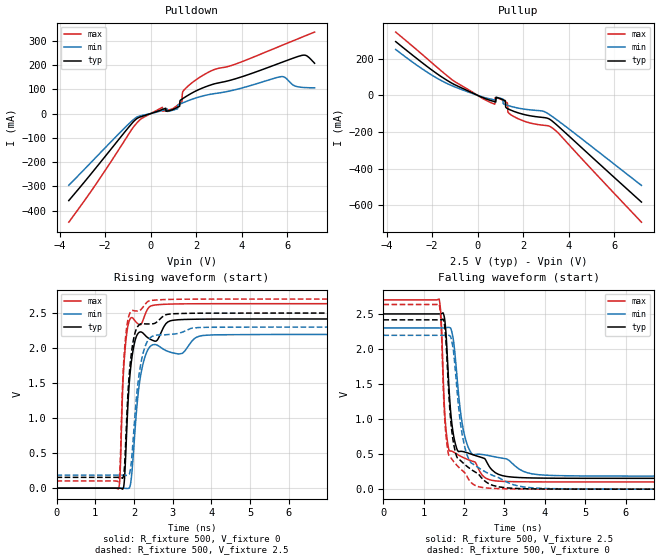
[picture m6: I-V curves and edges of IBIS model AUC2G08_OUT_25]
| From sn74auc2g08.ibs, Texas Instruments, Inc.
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[Model]   AUC2G08_OUT_25
Model_type  Output
Vref =   0
Rref =   500
Cref =   30p
Vmeas =   1.25
| variable   typ   min   max
C_comp   7.45pF   0.27pF   23.62pF
| C_pullup   8.36pF   0.27pF   23.62pF
| C_pulldown   6.53pF   1.89pF   15.75pF
[Temperature Range]   40   100   -40
| Ambient temperature   25   85   -40
[Voltage range]   2.5   2.3   2.7
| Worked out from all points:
|   slope of the pulldown table from 0 to 0.375 V, typ, clamps not added: 30.9 ohm
|   slope of the pullup table from 0 to 0.375 V, typ, clamps not added: 19.2 ohm
|   rising waveform, R_fixture 500, V_fixture 0: 20-80 % time 178ps typ, 248ps min, 131ps max; typ from 0 V to 2.42 V
|   falling waveform, R_fixture 500, V_fixture 2.5: 20-80 % time 223ps typ, 313ps min, 153ps max; typ from 2.5 V to 0.154 V
|   rising waveform, R_fixture 500, V_fixture 2.5: 20-80 % time 176ps typ, 247ps min, 129ps max; typ from 0.154 V to 2.5 V
|   falling waveform, R_fixture 500, V_fixture 0: 20-80 % time 238ps typ, 335ps min, 155ps max; typ from 2.42 V to 0 V
[Pulldown]
| AUC2G08_OUT_25
|   Voltage   I(typ)   I(min)   I(max)
-3.6V     -357.9mA   -295mA     -446.9mA
-445mV    -13.39mA   -9.086mA   -23.04mA
515mV     17.02mA    12.57mA    25.99mA
1.03V     19.04mA    15.49mA    23.85mA
1.27V     29.99mA    38.36mA    41.3mA
1.37V     59.29mA    42.41mA    48.87mA
1.395V    60.81mA    43.42mA    85.06mA
1.48V     65.92mA    46.77mA    98.72mA
2.545V    114.8mA    77.91mA    170.6mA
5.695V    208.4mA    151.5mA    277.8mA
6.74V     240.4mA    107.1mA    317.8mA
7.2V      207mA      105.9mA    335.2mA
[Pullup]
| AUC2G08_OUT_25
|   Voltage   I(typ)   I(min)   I(max)
-3.6V     293.6mA    250.5mA    345.5mA
-960mV    55.5mA     44.14mA    71.53mA
730mV     -33.82mA   -24.42mA   -47.21mA
760mV     -34.84mA   -25.13mA   -47.16mA
770mV     -35.18mA   -25.36mA   -13.07mA
1.115V    -23.84mA   -20.26mA   -27.67mA
1.215V    -28.81mA   -50.48mA   -34.67mA
1.295V    -71.05mA   -53.78mA   -40.2mA
1.345V    -74.3mA    -55.73mA   -93.3mA
1.755V    -94.43mA   -68.81mA   -126mA
3.31V     -143.6mA   -118mA     -180.4mA
7.2V      -582.7mA   -491.8mA   -692.5mA
[Ramp]
| AUC2G08_OUT_25
| variable   typ   min   max
dV/dt_r   1.46/1.79E-10   1.32/2.49E-10   1.59/1.31E-10
dV/dt_f   1.42/2.25E-10   1.27/3.13E-10   1.57/1.53E-10
R_load = 500
[Rising Waveform]
| AUC2G08_OUT_25
R_fixture =   500
C_fixture =   0
L_fixture =   0
V_fixture =   0
V_fixture_min = 0
V_fixture_max = 0
|   Time   V(typ)   V(min)   V(max)
0s        9.791nV    28.67nV    1.858nV
1.6ns     470.6uV    25.61uV    -8.929mV
1.64ns    -617.4uV   100.3uV    193.1mV
1.74ns    42.37mV    -167.3uV   1.761V
1.84ns    1.159V     -4.477mV   2.307V
1.93ns    1.795V     137.9mV    2.435V
2.055ns   2.156V     1.036V     2.37V
2.225ns   2.218V     1.756V     2.387V
2.485ns   2.11V      2.048V     2.609V
21.61ns   2.416V     2.195V     2.634V
[Falling Waveform]
| AUC2G08_OUT_25
R_fixture =   500
C_fixture =   0
L_fixture =   0
V_fixture =   2.5
V_fixture_min = 2.3
V_fixture_max = 2.7
|   Time   V(typ)   V(min)   V(max)
0s        2.5V       2.3V       2.7V
1.38ns    2.5V       2.3V       2.712V
1.435ns   2.503V     2.3V       2.376V
1.515ns   2.437V     2.299V     1.143V
1.62ns    1.496V     2.308V     567.3mV
1.785ns   644mV      1.859V     513mV
2.07ns    520.4mV    648.2mV    427.8mV
2.69ns    275mV      469.7mV    126.4mV
4.29ns    156.1mV    193.3mV    103.1mV
21.61ns   154.5mV    186.3mV    102.6mV
[Rising Waveform]
| AUC2G08_OUT_25
R_fixture =   500
C_fixture =   0
L_fixture =   0
V_fixture =   2.5
V_fixture_min = 2.3
V_fixture_max = 2.7
|   Time   V(typ)   V(min)   V(max)
0s        154.5mV    186.3mV    102.6mV
1.6ns     154.9mV    186.3mV    94.59mV
1.64ns    153.9mV    186.3mV    310.5mV
1.74ns    209.7mV    186.2mV    1.851V
1.83ns    1.207V     184mV      2.365V
1.915ns   1.843V     291mV      2.519V
2.025ns   2.213V     1.04V      2.531V
2.18ns    2.347V     1.789V     2.55V
2.4ns     2.345V     2.138V     2.675V
21.61ns   2.5V       2.3V       2.7V
[Falling Waveform]
| AUC2G08_OUT_25
R_fixture =   500
C_fixture =   0
L_fixture =   0
V_fixture =   0
V_fixture_min = 0
V_fixture_max = 0
|   Time   V(typ)   V(min)   V(max)
0s        2.416V     2.195V     2.634V
1.38ns    2.416V     2.195V     2.643V
1.435ns   2.417V     2.195V     2.288V
1.515ns   2.337V     2.194V     1.042V
1.61ns    1.472V     2.198V     502.7mV
1.815ns   467.1mV    1.48V      344.1mV
2.04ns    340.8mV    549.9mV    219.6mV
2.4ns     184.5mV    289.5mV    29.19mV
4.12ns    1.898mV    7.856mV    510.6uV
21.61ns   20.61uV    2.054uV    9.464uV
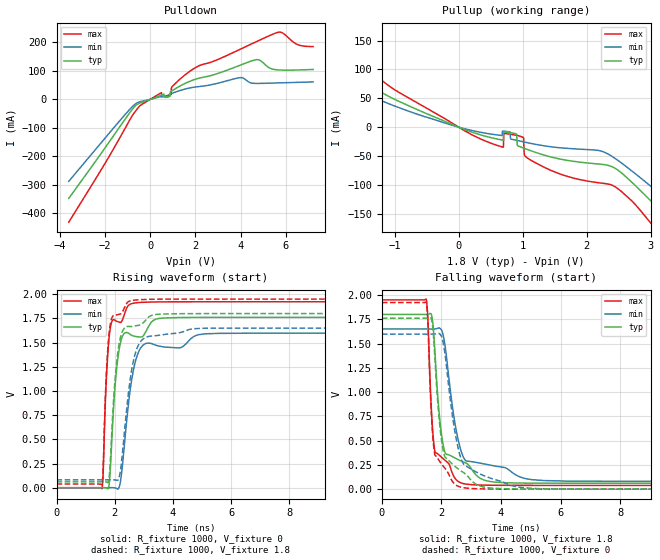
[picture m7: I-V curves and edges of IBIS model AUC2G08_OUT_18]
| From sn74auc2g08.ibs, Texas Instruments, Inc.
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[Model]   AUC2G08_OUT_18
Model_type  Output
Vref =   0
Rref =   1000
Cref =   30p
Vmeas =   0.9
| variable   typ   min   max
C_comp   6.69pF   0.25pF   21.38pF
| C_pullup   7.14pF   1.04pF   21.38pF
| C_pulldown   6.24pF   0.25pF   15.43pF
[Temperature Range]   40   100   -40
| Ambient temperature   25   85   -40
[Voltage range]   1.8   1.65   1.95
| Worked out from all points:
|   slope of the pulldown table from 0 to 0.27 V, typ, clamps not added: 34.4 ohm
|   slope of the pullup table from 0 to 0.27 V, typ, clamps not added: 24.7 ohm
|   rising waveform, R_fixture 1000, V_fixture 0: 20-80 % time 265ps typ, 394ps min, 176ps max; typ from 0 V to 1.76 V
|   falling waveform, R_fixture 1000, V_fixture 1.8: 20-80 % time 316ps typ, 478ps min, 197ps max; typ from 1.8 V to 0.061 V
|   rising waveform, R_fixture 1000, V_fixture 1.8: 20-80 % time 261ps typ, 385ps min, 173ps max; typ from 0.061 V to 1.8 V
|   falling waveform, R_fixture 1000, V_fixture 0: 20-80 % time 325ps typ, 487ps min, 197ps max; typ from 1.76 V to 0 V
[Pulldown]
| AUC2G08_OUT_18
|   Voltage   I(typ)   I(min)   I(max)
-3.6V     -347.6mA   -287.8mA   -431.2mA
-830mV    -38.94mA   -28.94mA   -62.22mA
-405mV    -11.33mA   -7.446mA   -19.55mA
495mV     14.95mA    10.62mA    23.51mA
885mV     12.26mA    19.06mA    15.87mA
925mV     28.54mA    20.16mA    16.88mA
960mV     30.1mA     21.15mA    44.31mA
2.045V    71.87mA    43.99mA    113.3mA
3.92V     118.2mA    75.85mA    173.7mA
4.625V    138.4mA    55.98mA    200.1mA
5.58V     103.9mA    57.6mA     233.8mA
7.2V      105mA      61.31mA    185.3mA
[Pullup]
| AUC2G08_OUT_18
|   Voltage   I(typ)   I(min)   I(max)
-3.6V     267.6mA    221.5mA    318.7mA
-2.61V    174.3mA    138.3mA    219.8mA
-2.13V    131.5mA    101.8mA    171.7mA
110mV     -4.812mA   -3.244mA   -7.318mA
695mV     -22.64mA   -6.826mA   -34.84mA
705mV     -8.168mA   -6.941mA   -10.57mA
980mV     -34.9mA    -24.66mA   -16.5mA
1.11V     -40.21mA   -27.81mA   -56.13mA
2.25V     -64.62mA   -42.31mA   -97.29mA
3.1V      -138.6mA   -111.4mA   -179.7mA
3.915V    -230.4mA   -188mA     -289.7mA
7.2V      -598mA     -503.3mA   -721.1mA
[Ramp]
| AUC2G08_OUT_18
| variable   typ   min   max
dV/dt_r   1.06/2.66E-10   0.97/3.99E-10   1.16/1.76E-10
dV/dt_f   1.05/3.18E-10   0.95/4.84E-10   1.15/1.97E-10
R_load = 1000
[Rising Waveform]
| AUC2G08_OUT_18
R_fixture =   1000
C_fixture =   0
L_fixture =   0
V_fixture =   0
V_fixture_min = 0
V_fixture_max = 0
|   Time   V(typ)   V(min)   V(max)
0s        7.669nV    26.14nV    1.117nV
1.56ns    64.98uV    -8.269uV   -10.1mV
1.72ns    -2.554mV   -8.452uV   1.171V
1.845ns   169.3mV    385.1uV    1.644V
1.995ns   981.1mV    -868.6uV   1.733V
2.15ns    1.424V     5.274mV    1.712V
2.595ns   1.574V     1.137V     1.903V
3.01ns    1.582V     1.482V     1.917V
5.085ns   1.761V     1.59V      1.922V
22.22ns   1.761V     1.597V     1.922V
[Falling Waveform]
| AUC2G08_OUT_18
R_fixture =   1000
C_fixture =   0
L_fixture =   0
V_fixture =   1.8
V_fixture_min = 1.65
V_fixture_max = 1.95
|   Time   V(typ)   V(min)   V(max)
0s        1.8V       1.65V      1.95V
1.49ns    1.8V       1.65V      1.958V
1.67ns    1.792V     1.649V     777.2mV
1.78ns    1.425V     1.65V      390.2mV
1.92ns    795.8mV    1.662V     352.3mV
2.09ns    409.4mV    1.538V     305.3mV
2.43ns    325.4mV    725.3mV    124.4mV
2.71ns    282.2mV    348.5mV    59.63mV
5.45ns    61.66mV    88.53mV    38.81mV
22.22ns   61.07mV    81.21mV    38.69mV
[Rising Waveform]
| AUC2G08_OUT_18
R_fixture =   1000
C_fixture =   0
L_fixture =   0
V_fixture =   1.8
V_fixture_min = 1.65
V_fixture_max = 1.95
|   Time   V(typ)   V(min)   V(max)
0s        61.05mV    81.2mV     38.68mV
1.56ns    61.11mV    81.2mV     29.36mV
1.72ns    58.86mV    81.2mV     1.216V
1.84ns    225.7mV    81.52mV    1.675V
1.98ns    988.8mV    80.99mV    1.783V
2.12ns    1.426V     81.25mV    1.79V
2.525ns   1.666V     1.104V     1.93V
2.975ns   1.704V     1.537V     1.945V
4.725ns   1.799V     1.644V     1.95V
22.22ns   1.8V       1.65V      1.95V
[Falling Waveform]
| AUC2G08_OUT_18
R_fixture =   1000
C_fixture =   0
L_fixture =   0
V_fixture =   0
V_fixture_min = 0
V_fixture_max = 0
|   Time   V(typ)   V(min)   V(max)
0s        1.761V     1.597V     1.922V
1.49ns    1.761V     1.597V     1.928V
1.54ns    1.761V     1.597V     1.747V
1.67ns    1.746V     1.597V     735.6mV
1.775ns   1.381V     1.598V     361.2mV
1.915ns   751.7mV    1.605V     298.3mV
2.07ns    381.2mV    1.49V      233.4mV
2.63ns    193.1mV    340.4mV    22.74mV
4.995ns   945.9uV    9.125mV    193.1uV
22.22ns   23.84uV    3.954uV    10.45uV
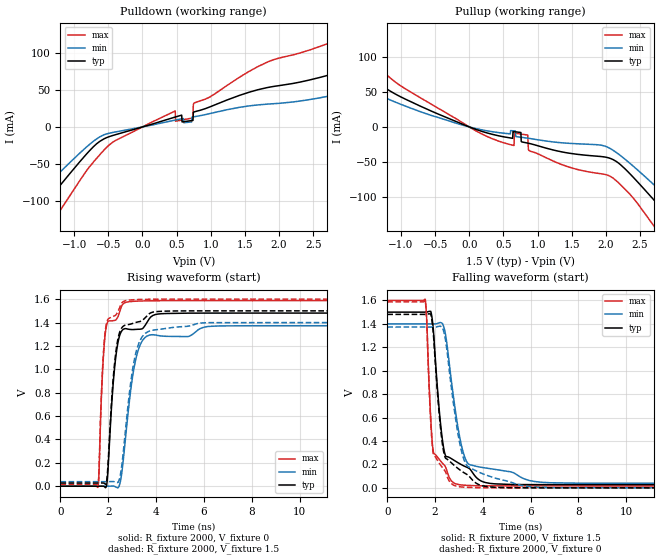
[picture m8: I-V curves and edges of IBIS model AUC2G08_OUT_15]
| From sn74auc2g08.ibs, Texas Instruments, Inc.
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[Model]   AUC2G08_OUT_15
Model_type  Output
Vref =   0
Rref =   2000
Cref =   15p
Vmeas =   0.75
| variable   typ   min   max
C_comp   6.42pF   1.69pF   19.05pF
| C_pullup   6.13pF   1.69pF   19.05pF
| C_pulldown   6.70pF   3.60pF   15.20pF
[Temperature Range]   40   100   -40
| Ambient temperature   25   85   -40
[Voltage range]   1.5   1.4   1.6
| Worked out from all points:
|   slope of the pulldown table from 0 to 0.225 V, typ, clamps not added: 36.6 ohm
|   slope of the pullup table from 0 to 0.225 V, typ, clamps not added: 29.5 ohm
|   rising waveform, R_fixture 2000, V_fixture 0: 20-80 % time 338ps typ, 511ps min, 214ps max; typ from 0 V to 1.48 V
|   falling waveform, R_fixture 2000, V_fixture 1.5: 20-80 % time 400ps typ, 611ps min, 232ps max; typ from 1.5 V to 0.027 V
|   rising waveform, R_fixture 2000, V_fixture 1.5: 20-80 % time 332ps typ, 503ps min, 211ps max; typ from 0.027 V to 1.5 V
|   falling waveform, R_fixture 2000, V_fixture 0: 20-80 % time 399ps typ, 617ps min, 230ps max; typ from 1.48 V to 0 V
[Pulldown]
| AUC2G08_OUT_15
|   Voltage   I(typ)   I(min)   I(max)
-3.6V     -343mA     -284.8mA   -423.7mA
-2.105V   -179.1mA   -144.1mA   -232.4mA
-1.795V   -144.7mA   -115.1mA   -192.1mA
-1.395V   -99.88mA   -78mA      -138.7mA
-395mV    -10.45mA   -6.753mA   -18.28mA
480mV     13.33mA    9.224mA    21.44mA
485mV     13.46mA    9.315mA    7.619mA
735mV     8.724mA    13.39mA    12.06mA
755mV     20.22mA    13.69mA    32.02mA
1.69V     50.03mA    29.61mA    81.13mA
3.34V     86.07mA    49.98mA    134.3mA
7.2V      80.6mA     45.5mA     141.2mA
[Pullup]
| AUC2G08_OUT_15
|   Voltage   I(typ)   I(min)   I(max)
-3.6V     254.2mA    195.1mA    304.8mA
-2.875V   187.5mA    148mA      233.8mA
-2.45V    149.7mA    116.2mA    192.1mA
-1.91V    104.4mA    79.22mA    139.6mA
100mV     -3.652mA   -2.395mA   -5.808mA
650mV     -6.722mA   -5.654mA   -26.6mA
855mV     -23.22mA   -16.17mA   -11.7mA
885mV     -23.88mA   -16.62mA   -34.51mA
2.105V    -46.97mA   -33.55mA   -73.62mA
2.76V     -111.3mA   -88.18mA   -150.1mA
3.36V     -178.2mA   -143.6mA   -230.9mA
7.2V      -605.9mA   -510.3mA   -734mA
[Ramp]
| AUC2G08_OUT_15
| variable   typ   min   max
dV/dt_r   0.90/3.39E-10   0.83/5.17E-10   0.96/2.15E-10
dV/dt_f   0.89/4.01E-10   0.82/6.15E-10   0.96/2.34E-10
R_load = 2000
[Rising Waveform]
| AUC2G08_OUT_15
R_fixture =   2000
C_fixture =   0
L_fixture =   0
V_fixture =   0
V_fixture_min = 0
V_fixture_max = 0
|   Time   V(typ)   V(min)   V(max)
0s        7.042nV    26.32nV    876.9pV
1.565ns   -3.333uV   -5.065uV   -10.27mV
1.765ns   181.9uV    -9.135uV   996.2mV
1.92ns    -2.01mV    -12.57uV   1.367V
2.305ns   1.09V      -5.886mV   1.421V
2.505ns   1.306V     39.63mV    1.509V
2.7ns     1.348V     369.4mV    1.57V
3.15ns    1.341V     1.086V     1.582V
3.715ns   1.433V     1.292V     1.586V
22.28ns   1.481V     1.373V     1.587V
[Falling Waveform]
| AUC2G08_OUT_15
R_fixture =   2000
C_fixture =   0
L_fixture =   0
V_fixture =   1.5
V_fixture_min = 1.4
V_fixture_max = 1.6
|   Time   V(typ)   V(min)   V(max)
0s        1.5V       1.4V       1.6V
1.59ns    1.5V       1.4V       1.609V
1.82ns    1.506V     1.4V       582.7mV
1.925ns   1.356V     1.399V     311mV
2.17ns    674.8mV    1.409V     244.6mV
2.36ns    339mV      1.377V     199mV
2.875ns   225.1mV    625.7mV    33.87mV
3.395ns   169.4mV    203.9mV    20.76mV
6.155ns   27.68mV    54.44mV    16.5mV
22.28ns   27.2mV     38.79mV    16.41mV
[Rising Waveform]
| AUC2G08_OUT_15
R_fixture =   2000
C_fixture =   0
L_fixture =   0
V_fixture =   1.5
V_fixture_min = 1.4
V_fixture_max = 1.6
|   Time   V(typ)   V(min)   V(max)
0s        27.17mV    38.78mV    16.4mV
1.565ns   27.17mV    38.77mV    7.068mV
1.76ns    27.43mV    38.77mV    1.003V
1.91ns    25.43mV    38.77mV    1.376V
2.295ns   1.11V      34.5mV     1.461V
2.49ns    1.325V     82.24mV    1.534V
2.685ns   1.376V     410.3mV    1.585V
3.15ns    1.4V       1.137V     1.596V
3.785ns   1.484V     1.331V     1.599V
22.28ns   1.5V       1.4V       1.6V
[Falling Waveform]
| AUC2G08_OUT_15
R_fixture =   2000
C_fixture =   0
L_fixture =   0
V_fixture =   0
V_fixture_min = 0
V_fixture_max = 0
|   Time   V(typ)   V(min)   V(max)
0s        1.481V     1.373V     1.587V
1.59ns    1.48V      1.373V     1.594V
1.815ns   1.484V     1.372V     575.9mV
1.92ns    1.335V     1.372V     298.6mV
2.155ns   672.4mV    1.379V     217.4mV
2.34ns    330.7mV    1.35V      163.8mV
2.84ns    185.5mV    618mV      17.77mV
3.345ns   113.2mV    188mV      4.531mV
5.755ns   670.4uV    15.28mV    120.9uV
22.28ns   28.18uV    5.072uV    11.59uV
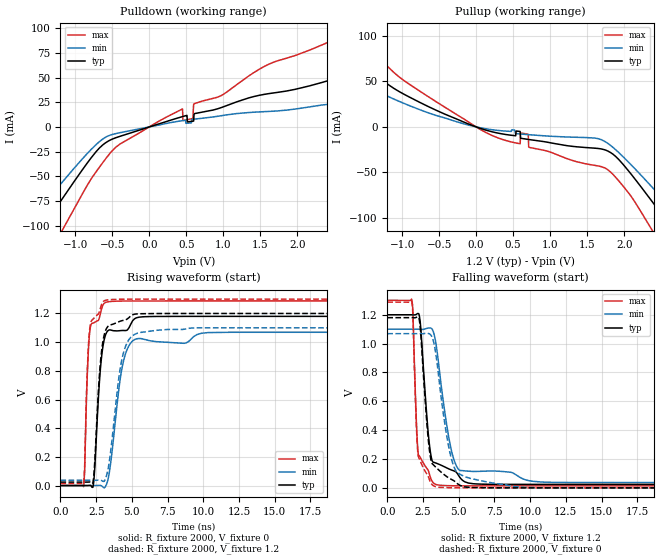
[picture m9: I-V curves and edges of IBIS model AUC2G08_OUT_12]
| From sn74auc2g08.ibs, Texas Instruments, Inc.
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[Model]   AUC2G08_OUT_12
Model_type  Output
Vref =   0
Rref =   2000
Cref =   15p
Vmeas =   0.6
| variable   typ   min   max
C_comp   5.93pF   2.37pF   15.74pF
| C_pullup   5.52pF   2.37pF   15.74pF
| C_pulldown   6.35pF   4.16pF   14.94pF
[Temperature Range]   40   100   -40
| Ambient temperature   25   85   -40
[Voltage range]   1.2   1.1   1.3
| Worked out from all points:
|   slope of the pulldown table from 0 to 0.18 V, typ, clamps not added: 42.3 ohm
|   slope of the pullup table from 0 to 0.18 V, typ, clamps not added: 38.7 ohm
|   rising waveform, R_fixture 2000, V_fixture 0: 20-80 % time 472ps typ, 799ps min, 279ps max; typ from 0 V to 1.18 V
|   falling waveform, R_fixture 2000, V_fixture 1.2: 20-80 % time 560ps typ, 952ps min, 288ps max; typ from 1.2 V to 0.024 V
|   rising waveform, R_fixture 2000, V_fixture 1.2: 20-80 % time 463ps typ, 791ps min, 273ps max; typ from 0.024 V to 1.2 V
|   falling waveform, R_fixture 2000, V_fixture 0: 20-80 % time 560ps typ, 958ps min, 284ps max; typ from 1.18 V to 0 V
[Pulldown]
| AUC2G08_OUT_12
|   Voltage   I(typ)   I(min)   I(max)
-3.6V     -338.3mA   -281.2mA   -417.3mA
-1.81V    -142.4mA   -113.5mA   -188.2mA
-1.485V   -106.7mA   -83.68mA   -145.8mA
-1.225V   -78.14mA   -60.24mA   -111.4mA
-715mV    -24.74mA   -17.64mA   -45.05mA
-390mV    -9.376mA   -5.759mA   -17.06mA
450mV     10.5mA     6.398mA    18.24mA
590mV     5.848mA    7.731mA    8.546mA
605mV     12.96mA    7.861mA    23.36mA
2.86V     55.94mA    19.09mA    100.7mA
3.425V    44.57mA    20.08mA    119.3mA
7.2V      57.06mA    26.82mA    108mA
[Pullup]
| AUC2G08_OUT_12
|   Voltage   I(typ)   I(min)   I(max)
-3.6V     224.6mA    100.8mA    291.5mA
-2.7V     158.6mA    66.17mA    205.2mA
-2.11V    110.3mA    77.88mA    148.7mA
-1.68V    77.88mA    55.75mA    108.7mA
-1.025V   38.18mA    27.56mA    53.97mA
50mV      -1.427mA   -842.9uA   -2.489mA
700mV     -13.68mA   -8.451mA   -7.891mA
1.78V     -26.5mA    -18.1mA    -47.09mA
2.4V      -84.34mA   -68.12mA   -116.4mA
2.695V    -116.7mA   -94.74mA   -156.1mA
3.045V    -155.5mA   -127mA     -202.8mA
7.2V      -615.6mA   -521.5mA   -745mA
[Ramp]
| AUC2G08_OUT_12
| variable   typ   min   max
dV/dt_r   0.72/4.78E-10   0.65/8.07E-10   0.78/2.82E-10
dV/dt_f   0.71/5.67E-10   0.64/9.58E-10   0.78/2.95E-10
R_load = 2000
[Rising Waveform]
| AUC2G08_OUT_12
R_fixture =   2000
C_fixture =   0
L_fixture =   0
V_fixture =   0
V_fixture_min = 0
V_fixture_max = 0
|   Time   V(typ)   V(min)   V(max)
0s        6.587nV    27.93nV    705.3pV
1.625ns   -4.087uV   -1.126uV   -7.953mV
1.965ns   323.3uV    -7.366uV   959.7mV
2.27ns    -12.49mV   -41.75uV   1.133V
2.78ns    792.5mV    1.251mV    1.191V
3.12ns    1.04V      -11.53mV   1.275V
3.475ns   1.085V     127mV      1.283V
4.335ns   1.081V     832.7mV    1.287V
5.185ns   1.163V     1.018V     1.287V
23.41ns   1.18V      1.069V     1.287V
[Falling Waveform]
| AUC2G08_OUT_12
R_fixture =   2000
C_fixture =   0
L_fixture =   0
V_fixture =   1.2
V_fixture_min = 1.1
V_fixture_max = 1.3
|   Time   V(typ)   V(min)   V(max)
0s        1.2V       1.1V       1.3V
1.72ns    1.2V       1.1V       1.3V
1.795ns   1.2V       1.1V       1.198V
2.06ns    1.205V     1.1V       395.4mV
2.21ns    1.206V     1.1V       225.1mV
2.915ns   327.6mV    1.108V     106.6mV
3.32ns    174.9mV    1.045V     27.14mV
4.355ns   129.2mV    321.4mV    14.99mV
5.065ns   74.39mV    121.6mV    14.22mV
23.41ns   24.01mV    36.66mV    13.87mV
[Rising Waveform]
| AUC2G08_OUT_12
R_fixture =   2000
C_fixture =   0
L_fixture =   0
V_fixture =   1.2
V_fixture_min = 1.1
V_fixture_max = 1.3
|   Time   V(typ)   V(min)   V(max)
0s        23.98mV    36.64mV    13.86mV
1.625ns   23.97mV    36.64mV    7.631mV
1.96ns    24.25mV    36.64mV    976.7mV
2.27ns    19.69mV    36.61mV    1.159V
2.755ns   805.6mV    37.89mV    1.224V
3.08ns    1.056V     32.09mV    1.289V
3.43ns    1.117V     173.7mV    1.296V
4.29ns    1.149V     874.8mV    1.299V
5.19ns    1.195V     1.054V     1.3V
23.41ns   1.2V       1.1V       1.3V
[Falling Waveform]
| AUC2G08_OUT_12
R_fixture =   2000
C_fixture =   0
L_fixture =   0
V_fixture =   0
V_fixture_min = 0
V_fixture_max = 0
|   Time   V(typ)   V(min)   V(max)
0s        1.18V      1.069V     1.287V
1.715ns   1.18V      1.069V     1.288V
1.79ns    1.18V      1.069V     1.192V
2.055ns   1.183V     1.069V     379.6mV
2.21ns    1.179V     1.069V     207mV
2.87ns    331mV      1.07V      77.87mV
3.235ns   158.8mV    1.014V     14.15mV
4.36ns    65.36mV    253.4mV    980.7uV
5.255ns   10.75mV    85.5mV     257.7uV
23.41ns   31.57uV    8.843uV    12.17uV
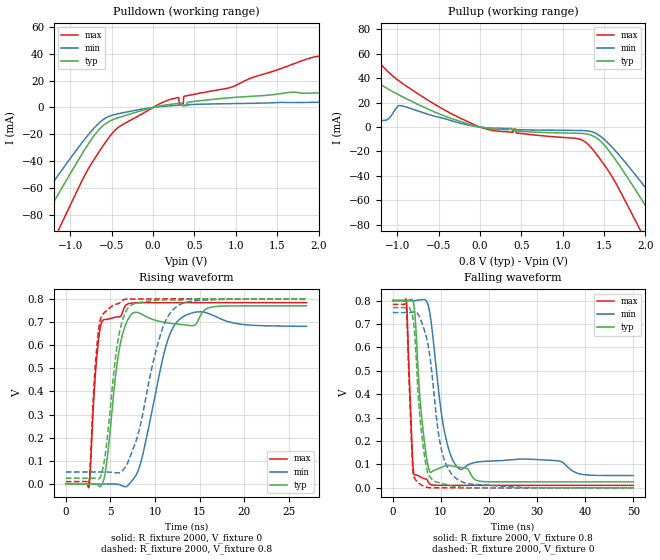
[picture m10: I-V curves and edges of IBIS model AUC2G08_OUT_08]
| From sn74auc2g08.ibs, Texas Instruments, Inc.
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[Model]   AUC2G08_OUT_08
Model_type  Output
Vref =   0
Rref =   2000
Cref =   15p
Vmeas =   0.4
| variable   typ   min   max
C_comp   5.67pF   2.72pF   7.64pF
| C_pullup   5.14pF   2.72pF   7.64pF
| C_pulldown   6.20pF   5.44pF   6.81pF
[Temperature Range]   40   100   -40
| Ambient temperature   25   85   -40
[Voltage range]   0.8   0.8   0.8
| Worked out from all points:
|   slope of the pulldown table from 0 to 0.12 V, typ, clamps not added: 77.1 ohm
|   slope of the pullup table from 0 to 0.12 V, typ, clamps not added: 92.8 ohm
|   rising waveform, R_fixture 2000, V_fixture 0: 20-80 % time 1.4ns typ, 2.21ns min, 817ps max; typ from 0 V to 0.77 V
|   falling waveform, R_fixture 2000, V_fixture 0.8: 20-80 % time 1.77ns typ, 2.85ns min, 868ps max; typ from 0.8 V to 0.025 V
|   rising waveform, R_fixture 2000, V_fixture 0.8: 20-80 % time 1.38ns typ, 2.64ns min, 762ps max; typ from 0.025 V to 0.8 V
|   falling waveform, R_fixture 2000, V_fixture 0: 20-80 % time 1.78ns typ, 2.85ns min, 863ps max; typ from 0.77 V to 0 V
[Pulldown]
| AUC2G08_OUT_08
|   Voltage   I(typ)   I(min)   I(max)
-3.6V     -332mA     -277.5mA   -406.5mA
-1.635V   -117.5mA   -94.15mA   -155.2mA
-1.375V   -89.26mA   -70.66mA   -121.5mA
-1.155V   -65.6mA    -51.21mA   -92.88mA
-630mV    -14.96mA   -10.34mA   -30.86mA
-430mV    -7.788mA   -4.786mA   -15.33mA
-90mV     -1.494mA   -794.3uA   -3.292mA
210mV     2.329mA    1.254mA    6.027mA
365mV     1.692mA    1.285mA    2.781mA
1.98V     10.83mA    3.867mA    38.03mA
2.365V    11.74mA    4.199mA    33.49mA
7.2V      23.85mA    8.894mA    59.33mA
[Pullup]
| AUC2G08_OUT_08
|   Voltage   I(typ)   I(min)   I(max)
-3.6V     79.74mA    9.11mA     185.5mA
-3.08V    78.24mA    9.441mA    162.7mA
-1.59V    27.55mA    11.02mA    82.8mA
-1.305V   38.33mA    6.645mA    59.6mA
-1.13V    31.97mA    5.759mA    46.58mA
-975mV    26.17mA    17.62mA    37.64mA
-245mV    4.854mA    3.296mA    7.479mA
1.36V     -7.061mA   -3.966mA   -18.08mA
1.875V    -50.9mA    -38.75mA   -76.11mA
2.115V    -76.5mA    -59.54mA   -107.8mA
2.405V    -108mA     -85.49mA   -146mA
7.2V      -633.7mA   -537.1mA   -765.1mA
[Ramp]
| AUC2G08_OUT_08
| variable   typ   min   max
dV/dt_r   0.47/1.41E-09   0.45/2.50E-09   0.48/8.22E-10
dV/dt_f   0.47/1.77E-09   0.45/2.85E-09   0.48/8.73E-10
R_load = 2000
[Rising Waveform]
| AUC2G08_OUT_08
R_fixture =   2000
C_fixture =   0
L_fixture =   0
V_fixture =   0
V_fixture_min = 0
V_fixture_max = 0
|   Time   V(typ)   V(min)   V(max)
0s        8.079nV    45.62nV    527.9pV
2.6ns     -54.02uV   -18.34uV   -11.52mV
3.405ns   297uV      -22.41uV   518.6mV
4.18ns    10.74mV    49.43uV    708.8mV
5.96ns    574.9mV    -1.845mV   722.3mV
7.41ns    735.6mV    14.6mV     781.6mV
8.515ns   733.7mV    109.6mV    783.3mV
11.28ns   697mV      603.6mV    783.6mV
12.75ns   690.2mV    711.5mV    783.7mV
27ns      770mV      681.2mV    783.7mV
[Falling Waveform]
| AUC2G08_OUT_08
R_fixture =   2000
C_fixture =   0
L_fixture =   0
V_fixture =   0.8
V_fixture_min = 0.8
V_fixture_max = 0.8
|   Time   V(typ)   V(min)   V(max)
0s        800mV      800mV      800mV
2.845ns   798.9mV    800mV      799mV
4.05ns    804.3mV    799mV      155.6mV
4.48ns    766.6mV    799.5mV    55.2mV
5.965ns   312.6mV    803.5mV    44.29mV
7.815ns   65.61mV    733mV      14.13mV
10.65ns   92.38mV    251mV      10.69mV
13.79ns   87.89mV    81.7mV     10.64mV
28.08ns   25.56mV    122.9mV    10.61mV
50ns      25.5mV     52.39mV    10.6mV
[Rising Waveform]
| AUC2G08_OUT_08
R_fixture =   2000
C_fixture =   0
L_fixture =   0
V_fixture =   0.8
V_fixture_min = 0.8
V_fixture_max = 0.8
|   Time   V(typ)   V(min)   V(max)
0s        25.46mV    52.25mV    10.6mV
2.565ns   25.44mV    52.25mV    3.931mV
3.655ns   22.79mV    52.35mV    660.9mV
4.305ns   96.69mV    52.41mV    740.3mV
4.97ns    321.3mV    51.74mV    763mV
5.82ns    615.3mV    48.37mV    778.9mV
6.815ns   751.5mV    82.37mV    799.1mV
10.59ns   794.8mV    642.9mV    799.9mV
12.21ns   795mV      760.2mV    799.9mV
27ns      799.9mV    797.3mV    800mV
[Falling Waveform]
| AUC2G08_OUT_08
R_fixture =   2000
C_fixture =   0
L_fixture =   0
V_fixture =   0
V_fixture_min = 0
V_fixture_max = 0
|   Time   V(typ)   V(min)   V(max)
0s        770mV      748.6mV    783.8mV
2.78ns    769.6mV    748.5mV    776.7mV
2.96ns    769.8mV    748.5mV    721.9mV
4.2ns     723.7mV    750.6mV    74.86mV
4.635ns   635.1mV    751.8mV    38.38mV
5.765ns   277.6mV    720.8mV    14.38mV
7.43ns    54.98mV    599.8mV    952.2uV
9.995ns   20.43mV    175.8mV    81.75uV
13.11ns   5.513mV    41.47mV    44.95uV
50ns      22.72uV    1.576uV    7.252uV
